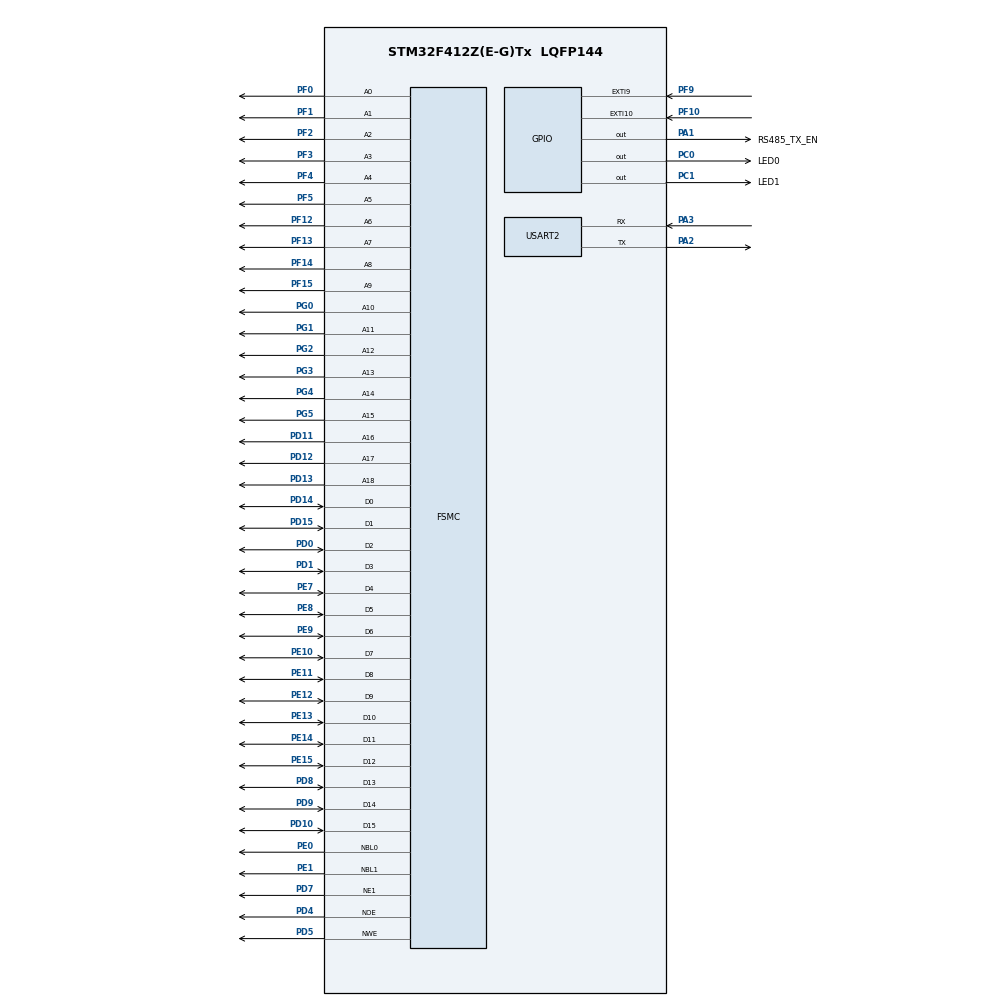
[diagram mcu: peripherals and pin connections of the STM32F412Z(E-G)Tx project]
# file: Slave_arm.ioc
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FSMC.AddressSetupTime1=0x00
FSMC.BusTurnAroundDuration1=0x00
FSMC.DataSetupTime1=0x06
FSMC.ExtendedAddressSetupTime1=0x00
FSMC.ExtendedBusTurnAroundDuration1=0x00
FSMC.ExtendedDataSetupTime1=0x06
FSMC.ExtendedMode1=FSMC_EXTENDED_MODE_ENABLE
FSMC.WriteFifo1=FSMC_WRITE_FIFO_DISABLE
FSMC.WriteOperation1=FSMC_WRITE_OPERATION_ENABLE
Mcu.Family=STM32F4
Mcu.Name=STM32F412Z(E-G)Tx
Mcu.Package=LQFP144
NVIC.EXTI15_10_IRQn=true\:2\:1\:true\:false\:true\:true\:true\:true
NVIC.EXTI9_5_IRQn=true\:3\:2\:true\:false\:true\:true\:true\:true
NVIC.PriorityGroup=NVIC_PRIORITYGROUP_2
NVIC.TIM2_IRQn=true\:3\:3\:true\:false\:true\:true\:true\:true
NVIC.TIM3_IRQn=true\:3\:1\:true\:false\:true\:true\:true\:true
NVIC.USART2_IRQn=true\:1\:3\:true\:false\:true\:true\:true\:true
PA1.GPIO_Label=RS485_TX_EN
PA1.GPIO_Speed=GPIO_SPEED_FREQ_HIGH
PA1.PinState=GPIO_PIN_SET
PA1.Signal=GPIO_Output
PA13.Mode=Serial_Wire
PA13.Signal=SYS_JTMS-SWDIO
PA14.Mode=Serial_Wire
PA14.Signal=SYS_JTCK-SWCLK
PA2.GPIO_ModeDefaultPP=GPIO_MODE_AF_PP
PA2.GPIO_PuPd=GPIO_NOPULL
PA2.GPIO_Speed=GPIO_SPEED_FREQ_HIGH
PA2.Mode=Asynchronous
PA2.Signal=USART2_TX
PA3.GPIO_ModeDefaultPP=GPIO_MODE_AF_PP
PA3.GPIO_PuPd=GPIO_PULLUP
PA3.GPIO_Speed=GPIO_SPEED_FREQ_HIGH
PA3.Mode=Asynchronous
PA3.Signal=USART2_RX
PC0.GPIO_Label=LED0
PC0.GPIO_PuPd=GPIO_PULLUP
PC0.GPIO_Speed=GPIO_SPEED_FREQ_HIGH
PC0.PinState=GPIO_PIN_SET
PC0.Signal=GPIO_Output
PC1.GPIO_Label=LED1
PC1.GPIO_PuPd=GPIO_PULLUP
PC1.GPIO_Speed=GPIO_SPEED_FREQ_HIGH
PC1.PinState=GPIO_PIN_SET
PC1.Signal=GPIO_Output
PC14-OSC32_IN.Mode=LSE-External-Oscillator
PC14-OSC32_IN.Signal=RCC_OSC32_IN
PC15-OSC32_OUT.Mode=LSE-External-Oscillator
PC15-OSC32_OUT.Signal=RCC_OSC32_OUT
PD0.GPIO_PuPd=GPIO_PULLDOWN
PD0.GPIO_Speed_High_Default=GPIO_SPEED_FREQ_HIGH
PD0.Signal=FSMC_D2_DA2
PD1.GPIO_PuPd=GPIO_PULLDOWN
PD1.GPIO_Speed_High_Default=GPIO_SPEED_FREQ_HIGH
PD1.Signal=FSMC_D3_DA3
PD10.GPIO_PuPd=GPIO_PULLDOWN
PD10.GPIO_Speed_High_Default=GPIO_SPEED_FREQ_HIGH
PD10.Signal=FSMC_D15_DA15
PD11.GPIO_PuPd=GPIO_PULLDOWN
PD11.GPIO_Speed_High_Default=GPIO_SPEED_FREQ_HIGH
PD11.Signal=FSMC_A16
PD12.GPIO_PuPd=GPIO_PULLDOWN
PD12.GPIO_Speed_High_Default=GPIO_SPEED_FREQ_HIGH
PD12.Signal=FSMC_A17
PD13.GPIO_PuPd=GPIO_PULLDOWN
PD13.GPIO_Speed_High_Default=GPIO_SPEED_FREQ_HIGH
PD13.Signal=FSMC_A18
PD14.GPIO_PuPd=GPIO_PULLDOWN
PD14.GPIO_Speed_High_Default=GPIO_SPEED_FREQ_HIGH
PD14.Signal=FSMC_D0_DA0
PD15.GPIO_PuPd=GPIO_PULLDOWN
PD15.GPIO_Speed_High_Default=GPIO_SPEED_FREQ_HIGH
PD15.Signal=FSMC_D1_DA1
PD4.GPIO_PuPd=GPIO_PULLDOWN
PD4.GPIO_Speed_High_Default=GPIO_SPEED_FREQ_HIGH
PD4.Signal=FSMC_NOE
PD5.GPIO_PuPd=GPIO_PULLDOWN
PD5.GPIO_Speed_High_Default=GPIO_SPEED_FREQ_HIGH
PD5.Signal=FSMC_NWE
PD7.GPIO_Speed_High_Default=GPIO_SPEED_FREQ_HIGH
PD7.Mode=NorPsramChipSelect1_1
PD7.Signal=FSMC_NE1
PD8.GPIO_PuPd=GPIO_PULLDOWN
PD8.GPIO_Speed_High_Default=GPIO_SPEED_FREQ_HIGH
PD8.Signal=FSMC_D13_DA13
PD9.GPIO_PuPd=GPIO_PULLDOWN
PD9.GPIO_Speed_High_Default=GPIO_SPEED_FREQ_HIGH
PD9.Signal=FSMC_D14_DA14
PE0.GPIO_Speed_High_Default=GPIO_SPEED_FREQ_HIGH
PE0.Signal=FSMC_NBL0
PE1.GPIO_Speed_High_Default=GPIO_SPEED_FREQ_HIGH
PE1.Signal=FSMC_NBL1
PE10.GPIO_Speed_High_Default=GPIO_SPEED_FREQ_HIGH
PE10.Signal=FSMC_D7_DA7
PE11.GPIO_Speed_High_Default=GPIO_SPEED_FREQ_HIGH
PE11.Signal=FSMC_D8_DA8
PE12.GPIO_Speed_High_Default=GPIO_SPEED_FREQ_HIGH
PE12.Signal=FSMC_D9_DA9
PE13.GPIO_Speed_High_Default=GPIO_SPEED_FREQ_HIGH
PE13.Signal=FSMC_D10_DA10
PE14.GPIO_Speed_High_Default=GPIO_SPEED_FREQ_HIGH
PE14.Signal=FSMC_D11_DA11
PE15.GPIO_Speed_High_Default=GPIO_SPEED_FREQ_HIGH
PE15.Signal=FSMC_D12_DA12
PE7.GPIO_Speed_High_Default=GPIO_SPEED_FREQ_HIGH
PE7.Signal=FSMC_D4_DA4
PE8.GPIO_Speed_High_Default=GPIO_SPEED_FREQ_HIGH
PE8.Signal=FSMC_D5_DA5
PE9.GPIO_Speed_High_Default=GPIO_SPEED_FREQ_HIGH
PE9.Signal=FSMC_D6_DA6
PF0.GPIO_Speed_High_Default=GPIO_SPEED_FREQ_HIGH
PF0.Signal=FSMC_A0
PF1.GPIO_Speed_High_Default=GPIO_SPEED_FREQ_HIGH
PF1.Signal=FSMC_A1
PF10.GPIO_PuPd=GPIO_NOPULL
PF10.Signal=GPXTI10
PF12.GPIO_Speed_High_Default=GPIO_SPEED_FREQ_HIGH
PF12.Signal=FSMC_A6
PF13.GPIO_Speed_High_Default=GPIO_SPEED_FREQ_HIGH
PF13.Signal=FSMC_A7
PF14.GPIO_Speed_High_Default=GPIO_SPEED_FREQ_HIGH
PF14.Signal=FSMC_A8
PF15.GPIO_Speed_High_Default=GPIO_SPEED_FREQ_HIGH
PF15.Signal=FSMC_A9
PF2.GPIO_Speed_High_Default=GPIO_SPEED_FREQ_HIGH
PF2.Signal=FSMC_A2
PF3.GPIO_Speed_High_Default=GPIO_SPEED_FREQ_HIGH
PF3.Signal=FSMC_A3
PF4.GPIO_Speed_High_Default=GPIO_SPEED_FREQ_HIGH
PF4.Signal=FSMC_A4
PF5.GPIO_Speed_High_Default=GPIO_SPEED_FREQ_HIGH
PF5.Signal=FSMC_A5
PF9.GPIO_PuPd=GPIO_NOPULL
PF9.Signal=GPXTI9
PG0.GPIO_Speed_High_Default=GPIO_SPEED_FREQ_HIGH
PG0.Signal=FSMC_A10
PG1.GPIO_Speed_High_Default=GPIO_SPEED_FREQ_HIGH
PG1.Signal=FSMC_A11
PG2.GPIO_Speed_High_Default=GPIO_SPEED_FREQ_HIGH
PG2.Signal=FSMC_A12
PG3.GPIO_Speed_High_Default=GPIO_SPEED_FREQ_HIGH
PG3.Signal=FSMC_A13
PG4.GPIO_Speed_High_Default=GPIO_SPEED_FREQ_HIGH
PG4.Signal=FSMC_A14
PG5.GPIO_Speed_High_Default=GPIO_SPEED_FREQ_HIGH
PG5.Signal=FSMC_A15
PH0\ -\ OSC_IN.Mode=HSE-External-Oscillator
PH0\ -\ OSC_IN.Signal=RCC_OSC_IN
PH1\ -\ OSC_OUT.Mode=HSE-External-Oscillator
PH1\ -\ OSC_OUT.Signal=RCC_OSC_OUT
ProjectManager.HeapSize=0x00000200
ProjectManager.StackSize=0x00001000
ProjectManager.TargetToolchain=STM32CubeIDE
RCC.AHBFreq_Value=100000000
RCC.APB1CLKDivider=RCC_HCLK_DIV2
RCC.APB1Freq_Value=50000000
RCC.APB1TimFreq_Value=100000000
RCC.APB2Freq_Value=100000000
RCC.APB2TimFreq_Value=100000000
RCC.CortexFreq_Value=100000000
RCC.HCLKFreq_Value=100000000
RCC.HSE_VALUE=25000000
RCC.PLLM=25
RCC.PLLN=400
RCC.PLLP=RCC_PLLP_DIV4
RCC.PLLSourceVirtual=RCC_PLLSOURCE_HSE
RCC.SYSCLKFreq_VALUE=100000000
RCC.SYSCLKSource=RCC_SYSCLKSOURCE_PLLCLK
RCC.USBFreq_Value=200000000
RCC.VCOOutputFreq_Value=400000000
SH.FSMC_A0.0=FSMC_A0,19b-a1
SH.FSMC_A1.0=FSMC_A1,19b-a1
SH.FSMC_A10.0=FSMC_A10,19b-a1
SH.FSMC_A11.0=FSMC_A11,19b-a1
SH.FSMC_A12.0=FSMC_A12,19b-a1
SH.FSMC_A13.0=FSMC_A13,19b-a1
SH.FSMC_A14.0=FSMC_A14,19b-a1
SH.FSMC_A15.0=FSMC_A15,19b-a1
SH.FSMC_A16.0=FSMC_A16,19b-a1
SH.FSMC_A17.0=FSMC_A17,19b-a1
SH.FSMC_A18.0=FSMC_A18,19b-a1
SH.FSMC_A2.0=FSMC_A2,19b-a1
SH.FSMC_A3.0=FSMC_A3,19b-a1
SH.FSMC_A4.0=FSMC_A4,19b-a1
SH.FSMC_A5.0=FSMC_A5,19b-a1
SH.FSMC_A6.0=FSMC_A6,19b-a1
SH.FSMC_A7.0=FSMC_A7,19b-a1
SH.FSMC_A8.0=FSMC_A8,19b-a1
SH.FSMC_A9.0=FSMC_A9,19b-a1
SH.FSMC_D0_DA0.0=FSMC_D0,16b-d1
SH.FSMC_D10_DA10.0=FSMC_D10,16b-d1
SH.FSMC_D11_DA11.0=FSMC_D11,16b-d1
SH.FSMC_D12_DA12.0=FSMC_D12,16b-d1
SH.FSMC_D13_DA13.0=FSMC_D13,16b-d1
SH.FSMC_D14_DA14.0=FSMC_D14,16b-d1
SH.FSMC_D15_DA15.0=FSMC_D15,16b-d1
SH.FSMC_D1_DA1.0=FSMC_D1,16b-d1
SH.FSMC_D2_DA2.0=FSMC_D2,16b-d1
SH.FSMC_D3_DA3.0=FSMC_D3,16b-d1
SH.FSMC_D4_DA4.0=FSMC_D4,16b-d1
SH.FSMC_D5_DA5.0=FSMC_D5,16b-d1
SH.FSMC_D6_DA6.0=FSMC_D6,16b-d1
SH.FSMC_D7_DA7.0=FSMC_D7,16b-d1
SH.FSMC_D8_DA8.0=FSMC_D8,16b-d1
SH.FSMC_D9_DA9.0=FSMC_D9,16b-d1
SH.FSMC_NBL0.0=FSMC_NBL0,2ByteEnable1
SH.FSMC_NBL1.0=FSMC_NBL1,2ByteEnable1
SH.FSMC_NOE.0=FSMC_NOE,Sram1
SH.FSMC_NWE.0=FSMC_NWE,Sram1
TIM2.AutoReloadPreload=TIM_AUTORELOAD_PRELOAD_ENABLE
TIM2.Period=1000-1
TIM2.Prescaler=100-1
TIM3.AutoReloadPreload=TIM_AUTORELOAD_PRELOAD_ENABLE
TIM3.Period=10000-1
TIM3.Prescaler=50-1
USART2.VirtualMode=VM_ASYNC
VP_TIM2_VS_ClockSourceINT.Mode=Internal
VP_TIM3_VS_ClockSourceINT.Mode=Internal
board=custom

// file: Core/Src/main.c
/* USER CODE BEGIN Header */
/**
  ******************************************************************************
  * @file           : main.c
  * @brief          : Main program body
  ******************************************************************************
  * @attention
  *
  * Copyright (c) 2024 STMicroelectronics.
  * All rights reserved.
  *
  * This software is licensed under terms that can be found in the LICENSE file
  * in the root directory of this software component.
  * If no LICENSE file comes with this software, it is provided AS-IS.
  *
  ******************************************************************************
  */
/* USER CODE END Header */
#include "main.h"
#include "tim.h"
#include "usart.h"
#include "gpio.h"
#include "fsmc.h"

/* USER CODE BEGIN Includes */
#include "sys.h"
#include "led.h"
#include "KesaiAPI.h"
#include "comm.h"
#include "base.h" /* 基本结构 */
#include "stdio.h"
#include "stdafx.h"
//#include "KS_FB_VISU.h"/* VISU相关 */
#include "KS_FB_ProSample.h"/* 采样处理及计算误�??? */
#include "KS_FB_ProSample_v2.h"
//新飞点剔除模块(总开关KS_USE_NEW_FLY_REMOVE在此头文件内)|Yang.zj+用于新飞点检测 2026.10.24.103254
#include "ks_fly_remove.h"
//#include "AutoFindTaps.h"
#include "calcerr.h"
#include "calcbase.h"
/* 2024.02.01.110058 同步 liu.yt */
#include "StRingNet.h"  /* 2024.1.18.153154/han.dp/+ */
#include "StFileOp.h"
#include "bin_upgrade.h"
#include "ks_somefunc.h"

//2025.7.22.105132|wei.n
#include "modbus485.h"
#include "KS_FB_RoundSample.h"/*粗采样处理及显示处理*/
#include "KS_FB_DacOutCtl.h"
#include "string.h"
//全自动套印色标检测(总开关USE_MARK_DETECTION在markDetection.h,暂未投用默认0整体不编译;
//include必须无条件保留——宏定义在头文件内,若此处也加#if会把宏锁死在未定义(恒0),启用失效
// |Yang.zj+markDetection封编译宏 2026.11.13.120400)
#include "markDetection.h"

// 2026.5.20.100908 宏定义：1 = 使用新版 KS_FB_ProSample_V2，0 = 使用旧版 KS_FB_ProSample，
#define USE_PROSAMPLE_V2  0

/* USER CODE END Includes */

/* USER CODE BEGIN PV */

EXCEPTION_OF_CRASH exception_crash;/* 主机死机信息/2024.1.20.142743/han.dp/+ */
uint8_t byReqRdExceptionOfProgCrash = 0;/* =1.send Mailbox cmd to master-station. and echo ack message./2024.1.18.105623/han.dp */
unsigned char g_bygetsts = 0;/* =0 idle =1 给上位机信号 抓取死机信息 */
							 /* =2 获取抓取到信�??? =3 获取成功 =4 获取超时@10�??? */
unsigned short g_getcrash_inf_timecnt_10ms = 0;/* 10ms计时计数值@用于获取死机信息计时 */
char g_send_crashinf_hmi = 0;

static WORD g_wCnt_Rs = 0;
static INT g_iRtn_Calc2022 = 0;
static INT g_aiVResult[2] = {0};
static INT g_aiHResult[2] = {0};

INT Perimeter = 500;
INT Coordinate = 4000;
static BYTE iStationId=240;                                         /* 站号获取 */
/* 2021.8.14.152254=-------------------------------------------------2021.8.14.152306判断定时器无标志，只做计数增�??? */
static WORD g_wCount_Comm;											/* 主从通讯 */
//static WORD g_wCount_Visu;											/* 485通讯 */
static WORD g_wCount_CaseBase;										/* 计算基线 */
//static WORD g_wCount_TimeOut;										/* 485超时计数 */
static WORD g_wCount_FeedDog;										/* 喂狗计数 */
static WORD g_iCount_TimeOutNum;									/* 超时计次 */
static WORD g_uiDelayTime_Init=0;//2025.7.25.160145+
static WORD g_uiTime_DigitalTubes=0;								/*2025.09.06.151705//xi.hy//数码管显示计数*/
static WORD g_uiTime_LED1_Flick=0;//2025.11.5.183542+

//2025.11.28.130828//自动聚焦_偏移自调整相关计数变量
static WORD g_uiTime_OffsetAutoCtl;//偏移自调整控制计数
static WORD g_uiTime_xBaseDone_OffsetAutoCtl;//基线稳定计数
static DWORD g_dwRemainTime_OffsetCtl;//本次调整持续时间
//2025.12.01.165834//自动聚焦_光源自调整相关计数变量
static WORD g_uiCtlTime_SourceLightCtl;//光源控制时间计数
static WORD g_uiTime_PeakDone_SourceAutoCtl;//光源控制到目标时间计数
static DWORD g_dwRemainTime_SourceCtl;//本次光源自调持续时间计数
//INT aiFineData1[4000];												/* 精采样�?? */
//INT aiFineData2[4000];												/* 精采样�?? */
unsigned short tmp;
//extern unsigned char byReceiveEnd;									/* 接收完成标志，根据接收数据量与CRC校验判断 */
//extern DWORD dwRoundSampleThreshold;								/* 主站接收到的粗采样阀�???*/
uint8_t* pbyRoundData2;												/* 粗采样第二路信号地址**便于保存文件 */
uint8_t* pbyRoundData1;												/* 粗采样第�???路信号地�???**便于保存文件 */
static BYTE byFineSampleSaveFlag;									/* 主站下发的保存采样按�???*/
static INT aiError_V[40];											/* 2020.05.04.171022|niu.j|误差存入循环队列，等待发送时读取索引，判断误差刷新幅数，根据幅数发�?�误差个�???*/
static INT aiError_H[40];
static BYTE byScanCount=0;
//static BYTE byScanCountPre=0;
static unsigned short FeedDogAdr=0x054;								/* 喂狗地址*/
static unsigned short FeedDog=0x5555;								/* 喂狗�???*/
static unsigned short wArmResetCountAdr=0x500;						/* 看门狗复位计数地�??? */
static unsigned short wArmResetCount;								/* 看门狗复位计�??? */
static REAL alrThreshold[2];										/* 采样显示�???�??? */
static REAL alrBase_Fs[2];											/* 精采样计算基�??? */
INT iRtnRdID;
//extern BYTE RS485_RX_BUFF[150];										/* 读取到的485数据 */
WORD ErrNum;														/* 错误计次 */
//BYTE abyRoundSampleData_485[1600];									/* 发�?�波形使用缓冲区 */
//static BYTE abyMinData_Sample[2] ;									/* 两路信号�???小�??-2021.9.16.105149通讯到人机处理波形显�??? */

//extern WORD wSendNum_Test;											/* 485发�?�计�???2021.8.20.103739 */
//extern WORD wReadNum_Test;											/* 485接收计次2021.8.20.103749 */
//2025.7.23.104353+
static uint8_t bySignalSelect_Pre = 0 ;
static uint16_t ChangeRGBAdr = 0x5040;							//切换RGB通道的地址
uint16_t uiValue_RGB = 0;
/* 2023.09.18.113506 定义 */
unsigned int dwAdrStAutoFind_wwz_IN,dwAdrStAutoFind_wwz_OUT;

//2025.7.23.195236 移动到全局@就相当于对结构体初始化
StAxisParam stStAxisParam;													/* 轴参�??? */
StGrpParam stStGrpParam;														/* 系参�??? */
StGlobalParam stStGlobalParam;												/* 整机参数 */
StSyncWithServerOut stStSyncWithServerOut;									/* 通讯相关变量 */
StPara_PduBroadcastUp stStPara_PduBroadcastUp;								/* 通讯数据|UP */
StPara_PduBroadcastDn stStPara_PduBroadcastDn;								/* 通讯数据|Dn */
/* USER CODE END PV */

void SystemClock_Config(void);
/* USER CODE BEGIN PFP */
/* 2024.02.01.155049 死机时获取信息函�??? */
/* pxgeten 使用的轴参数中的i_pstStAxisParam->wButtonFun.15| */
void ks_get_prgcrash_inf(short iStationId,/* 本地站号的接口好像没用，先留�???�??? */
						char* pxgeten,
						unsigned char* pbygetsts,
						unsigned short* pgetcrash_inf_timecnt_10ms,
						LP_EXCEPTION_OF_CRASH pcrash_inf)
{
	unsigned char bygetsts,xgeten;
	unsigned short crash_inf_adrsa = 0x3e00;/* 死机信息的起始地�??? */
	unsigned short getcrash_inf_timecnt_10ms;
	static unsigned char timeout_cnt;/* 超时计数 */
	StFunction get_inf;/* 获取死机信息时需要发送的内容结构体@主要是m_id=0x400; */
	get_inf.m_id = 0x400;
	/* 计算dword的个�??? */
	signed int inf_lenth=sizeof(EXCEPTION_OF_CRASH);
	if(inf_lenth % 4 ==0 ) inf_lenth = inf_lenth/4;
	else inf_lenth = inf_lenth/4+1;

	if(pbygetsts!=0 && pcrash_inf!=0 && pxgeten!=0 &&  pgetcrash_inf_timecnt_10ms!=0)
	{
		bygetsts = *pbygetsts;/* 拿到当前状�?�|=1 向主站写入获取命令�?��?? */
		xgeten = *pxgeten;
		getcrash_inf_timecnt_10ms = *pgetcrash_inf_timecnt_10ms;
		if(xgeten)
		{/* 获取标志有效�??? */
			xgeten = 0;
			if(bygetsts==3 || bygetsts==4 || bygetsts==0)/* 在初始状�???,或着完成状�?�|超时状�?�可以重新开�??? */
				bygetsts = 1;
		}
		else
		{/* 未使�??? */
			;
		}
		switch (bygetsts)
		{
			case 0:/* 初始状�?? */
				break;
			case 1:/* 向主站写入获取命�??? */
				/* 给主站触发请�???,通过mailbox通讯 */
				GT_RN_DevicePcMailComWr((unsigned long *) & (get_inf), 0, 0, 2, RN_LMWR, 1);/* RN_LMWR 起始地址无意�??? */
				/* inf_lenth 这个变量是dword的个�???,使用sizeof获取@2024.06.07.090154 */
				memset((void*)pcrash_inf,0,(int32)(sizeof(EXCEPTION_OF_CRASH))/*inf_lenth*/);/* 初始化信�??? */
				bygetsts = 2;
				getcrash_inf_timecnt_10ms =0 ;/* 清零计时�??? */
				timeout_cnt = 0;
				break;
			case 2:/* 定时�???�??? 获取的信息写入区域@起始地址0x3E00 */
				if(getcrash_inf_timecnt_10ms>=100)/* 100*10ms */
				{
					getcrash_inf_timecnt_10ms = 0;
					GT_RN_DevicePcMailComRd((unsigned long *) pcrash_inf, 0, crash_inf_adrsa, inf_lenth, RN_ARD);/* RN_ARD |绝对寻址 */
					if(pcrash_inf->wYear!=0)/* 获取到了信息*/
					{
						bygetsts = 3;
					}
					else
					{
						timeout_cnt = timeout_cnt+1;/* 超时+1*/
					}

					if (timeout_cnt>=10)/* 10次超�???*/
					{
						bygetsts = 4;
					}
				}
				break;
			case 3:/* 获取完成�??? */
				break;
			case 4:/* 获取超时�???*/
				break;
			default:
				break;
		}
		*pbygetsts = bygetsts;
		*pxgeten = xgeten;
		*pgetcrash_inf_timecnt_10ms = getcrash_inf_timecnt_10ms;
	}
}
/* ********************************************************获取死机信息@2024.02.01.224710-end */

/* 2024.9.28.141504/wei.n/外部中断的回调函数 */
void HAL_GPIO_EXTI_Callback(uint16_t GPIO_Pin)
{
	if(GPIO_Pin == GPIO_PIN_9)
	{
		__HAL_GPIO_EXTI_CLEAR_IT(EXTI_LINE_9); /* 清除LINE9上的中断标志位 */
	}
	else
	{
		__HAL_GPIO_EXTI_CLEAR_IT(EXTI_LINE_10); /* 清除LINE10上的中断标志位 */
		RingNetRxPacketThread(0);
	}
}

/* +注释 10ms计时器@2024.02.01.221826 */
/* 2024.7.31.115331/wei.n/TIM3的中断函�??? */
//已经验证过了,time3的计时周期为10ms@2025.11.5.125252确认
//调整一些计时的宏
void TIM3_IRQHandler(void)
{
	//2025.11.5.125159+
	//获取更新中断宏使用错误@用成了更新中断使能标志获取宏
	//if(__HAL_TIM_GET_IT_SOURCE(&htim3, TIM_IT_UPDATE) == SET)  /* 溢出中断 */
	if(__HAL_TIM_GET_FLAG(&htim3, TIM_FLAG_UPDATE) )//更新中断有效
	{
		__HAL_TIM_CLEAR_FLAG(&htim3, TIM_FLAG_UPDATE);//清除更新中断标志
		HAL_TIM_IRQHandler(&htim3);

		g_wCount_Comm= g_wCount_Comm+1;
		//g_wCount_Visu= g_wCount_Visu+1;
		g_wCount_CaseBase= g_wCount_CaseBase+1;
		g_wCount_FeedDog= g_wCount_FeedDog+1;
		/* 2024.02.01.221659 增加获取死机信息计时�??? */
		g_getcrash_inf_timecnt_10ms = g_getcrash_inf_timecnt_10ms+1;

		//2025.7.22.175420+
		g_uiCycleCommTimer = g_uiCycleCommTimer + 10;//485通讯计时@5ms
		g_uiTimeOutTimer += 10;//通讯超时计时
		g_uiPollTimer += 10;//轮询计时
		//2025.7.25.155941 初始化等待@月光宝盒\月光宝盒pro中站号的eerom启动比较慢,增加个延时再读取|临时方案
		g_uiDelayTime_Init += 10;

		//数码管显示站号轮询
		//2025.09.06.141720//xi.hy
		g_uiTime_DigitalTubes += 10;

		g_uiTime_LED1_Flick += 10;
		//LED0 = !LED0;

		//自动聚焦_偏移自调整计数
		g_uiTime_OffsetAutoCtl+=10;
		g_uiTime_xBaseDone_OffsetAutoCtl+=10;
		g_dwRemainTime_OffsetCtl+=10;
		//自动聚焦_光源自调整计数
		g_uiCtlTime_SourceLightCtl+=10;//光源控制时间计数地址
		g_uiTime_PeakDone_SourceAutoCtl+=10;//光源控制到目标时间计数地址
		g_dwRemainTime_SourceCtl+=10;//本次光源自调持续时间计数地址
	}
	//2025.11.5.124942 清除的宏定义使用错误
	//__HAL_TIM_CLEAR_IT(&htim3, TIM_IT_UPDATE);  /* 清除中断标志�??? */
}

/* USER CODE END PFP */

int main(void)
{

  /* MCU Configuration--------------------------------------------------------*/

  /* Reset of all peripherals, Initializes the Flash interface and the Systick. */
  HAL_Init();

  /* Configure the system clock */
  SystemClock_Config();

  /* Initialize all configured peripherals */
  MX_GPIO_Init();
  /* USER CODE BEGIN 2 */
  //HAL_NVIC_SetPriorityGrouping(NVIC_PRIORITYGROUP_2);/* 设置系统中断优先级分�???2 */
  MX_LED_Init();									 /* LED初始�??? */
  MX_FSMC_Init();
  GTD_Open(Bank1_SRAM3_ADDR);
  tmp = 0;

  MX_USART2_UART_Init(); 	/* 485初始化，APB1时钟1/4系统时钟频率,25HZ */
  MX_TIM3_Init();   		/* 10ms */
  MX_TIM2_Init();			/* 该定时器用于增加接收与发送数据包之间的间�???-100us-1000us,根据设定值不�??? */

  /********************************************************/

  while(iStationId<1 || iStationId>31)				/* 站号读取成功 */
  {
	  if(g_uiDelayTime_Init >= 1000)//超过1s后执行 EEROM启动有点慢 临时处理@针对月光宝盒\月光宝盒pro|2025.7.25.160355
	  {
		  //g_uiDelayTime_Init = 1000;//防止溢出
		  iRtnRdID= GT_RN_GetLocalID(&iStationId);
	  }

  }

	while( (tmp & 0x4000) == 0x0000)					/* 读取主站DSP启动标志 */
	{
		if(g_uiDelayTime_Init>1000)//2025.11.29.155702+增加1s sleep|没开主站的时候有可能在线升级不成功
		{
			g_uiDelayTime_Init = 0;//2025.11.29.155802+ 重新计时
			iRtnRdID = GT_RN_MailRdMultReg(2, &tmp, 1, 1, 0);
			if(iRtnRdID)
			{
				tmp = 0;
			}
			/* 从站等待主站响应过程中，�???直喂�??? */
			GT_RN_WriteFPGA(FeedDogAdr, &FeedDog);
		}
	}

  /* 用于看门狗计�??? */
  GT_RN_ReadFPGA(wArmResetCountAdr,&wArmResetCount);							/* 从FPGA中先读出计数�??? */
  wArmResetCount=wArmResetCount+1;
  GT_RN_WriteFPGA(wArmResetCountAdr,&wArmResetCount);							/* +1后再写入进去 */
 //激活本地粗采样
  KS_InitSample(iStationId);
  static BYTE xGetAxisId;														/* 获取站号 */
  BYTE byLedSwitchTimeouts;														/* 屏保延时 */
 // static INT iJourney_HorzRapidAdjust;											/* 横向快�?�丢�??? */
  //static DWORD  dwPlateAdjustmentProf;											/* 快�?�对版�?? */
  INT iRoundSampleFlag;															/* 实际粗采样数据采集到�??? */
  INT iFineSampleFlag;															/* 实际精采样数据采集到�??? */
  static BYTE xStart;															/* 程序首次运行标志 */
  uint8_t* pbyFineData2;															/* 粗采样第二路信号地址 */
  uint8_t* pbyFineData1;															/* 粗采样第�???路信号地�??? */
  static REAL alrBase[2];														/* 两路波形的基�??? */
  static REAL alrBase_HMI[2];													/* 两路波形的基�??? */
  static BYTE xInclNegative10vSignal;											/* 处理±10V电眼 */
  INT iN;																	/* 循环变量 */
  INT* piItem1;
  INT* piItem2;
  static INT aiFineSample_Data[9];												/* 通讯给主站的波形细节 */
  static BYTE bySignal10VCoef;													/* ±10V光电眼IO控制 */
  BYTE xFlag_CopyFromMaster;													/* 主站参数更新完成标志，用�???485通讯使能 */

  BYTE xOK_FromMaster;
  static BYTE test;

  //BYTE bySample_Interval;														/* 采样间隔-放大�???2，不放大5 */
  static BYTE xFlag_SingleMode;
  //BYTE xMarkHor;																/* 门内基线标志 */
  DINT diFineSampleStart;
  INT iGateWidthFinePt = 1000;//精彩样点数值@2025.7.15.183713+
	// 2025.7.22.103936|wei.n|添加
	uint8_t*	pbyRoundData1;									/*粗采样第�???路信号地�???*/
	uint8_t*	pbyRoundData2;									/*粗采样第二路信号地址*/
	uint8_t*	pbyRoundData3;									/*粗采样第�???路信号地�???*/
	uint8_t*	pbyRoundData4;									/*粗采样第二路信号地址*/
	uint8_t*	pbyRoundData5;									/*粗采样第�???路信号地�???*/
	uint8_t*	pbyRoundData6;
	uint8_t xCalcBaseLine = FALSE;
	uint8_t xUpdateRsData_Hmi = FALSE;//更新界面粗采样数据
	uint8_t xDealRsData = FALSE;
	uint8 byRoundId = 0;//当前粗采样轮询id
	uint8_t bySignalSelect_Cur = 0;//当前轮询RGB通道
	uint8_t byChannel_T1T2_Cur = 0;//当前轮询T1 T2通道
	uint8_t xDealRsDataDne = FALSE;
	//2025.12.03.152331//自动聚焦相关局部变量定义
	uint8_t xFindFSPeak_SourceLightCtl=FALSE;

  bySignalSelect_Pre = stStGlobalParam.bySignalSelect +1 ;//上电后写入一次

  while (1)
  {

	//在20ms周期任务中执行@2025.6.11.124050+
	//油墨槽脉冲输出控制变量定义
	BYTE xPulseCtlEn = FALSE;//脉冲控制使能
	BYTE xPulseOutEn_Act = FALSE;//脉冲输出使能了
	BYTE xMoveDir_Act = FALSE;//运动方向
	BYTE xPulseCtlMode_Act = FALSE;//脉冲控制模式
	BYTE xVelMod_Run_Act = FALSE;//速度模式,速度使能标志
	REAL rVelMod_Vel_Act = 0;//速度模式下的速度
	WORD wPosMod_Pulse_Act = 0;//位置模式下实际的脉冲数
	WORD wPulse_1r = 0;//1圈的脉冲数
	WORD wTmp = 0;
	//DINT diThisMovePluse = 0;//2025.6.11.232404 本次运动的距离
	Lp_StInkGrooveCtl pstStInkGrooveCtl = 0;

	  /* ----------------------------------------------------sj 2021.8.20.105400--------------�???部变量定义完�???--------------------------- */
	  //2025.09.06.151737//xi.hy//数码管显示站号处理
	  KS_ShowId_DigitalTubes(iStationId,
			  	  	  	  	  &g_uiTime_DigitalTubes,
							  xFlag_CopyFromMaster);

		//运行指示(LED1)@2025.10.29.164927+
		if(xFlag_CopyFromMaster)//主站通讯成功按照500ms闪烁@周期是1s
			KS_Led1Flick(500,&g_uiTime_LED1_Flick);
		else//运行了就按照2s闪烁@周期是4s
			KS_Led1Flick(2000,&g_uiTime_LED1_Flick);

	  /* 2022.6.21.090345 -判断站号31�???-不进入以下�?�辑-进入到副主站485通讯 */
	  if(iStationId!=31)//2025.7.24.203934 增加了主站通讯完成标志
	  {
		  //2025.11.4.114411 屏蔽
		  //GT_RN_SetSenceDO((WORD)bySignal10VCoef);								/* ±10V光电眼两路IO控制 */
		  //bySample_Interval = 5;
		  /* 主�?�辑里面500ms喂一次狗 */
		  if(g_wCount_FeedDog>=50&&test==0)
		  {
			  GT_RN_WriteFPGA(FeedDogAdr, &FeedDog);
			  g_wCount_FeedDog=0;
		  }

		/* 看门�???-喂狗结束2021.8.20.105514 */

		/* -----------------------------2021.1.5.153657---------横排打开后，基线�???要用精采样基线，获取门内基线�???�??? */
		//xMarkHor = GetBit(stStAxisParam.wSwitchRef,1);
		//xMarkHor = KSGetDataBit(&stStAxisParam.wSwitchRef,1);
		/* -----------------------------------------------------计算偏移�??? */
		stStAxisParam.iARMRunNum=0;		/* 2022.5.21.084425 */
		/* 2021.8.20.112017-------------------------------------粗采样处�???--------------------------------------- */
		/* 读取粗采样数据有效标�??? */
		//GT_RN_SampleGetRoundData((void**)&pbyRoundData2, (void**)&pbyRoundData1, &iRoundSampleFlag);
		//2025.7.22.102737|wei.n|移植
		GT_RN_SampleGetRoundData((void**)&pbyRoundData1, (void**)&pbyRoundData2, (void**)&pbyRoundData3, (void**)&pbyRoundData4, (void**)&pbyRoundData5, (void**)&pbyRoundData6, &iRoundSampleFlag);
		/* 粗采样数据到位后，每500ms处理�???次数�??? */
		/* 1.计算粗采样基�??? */
		/* 2.将两路信号处理为HMI显示�???用数�??? */

		//xUpdateRsData_Hmi = FALSE;
		if ( iRoundSampleFlag == 1 && !xDealRsData)//2025.9.2.122029+xDealRsData
		{
			stStAxisParam.uiRSampleCounter +=1;
			iRoundSampleFlag = 0;//清零粗采样标志
			//xUpdateRsData_Hmi = TRUE;//更新粗采样界面数据
			xDealRsData = TRUE;//处理粗采样数据@2025.8.6.183048+

			stStAxisParam.iARMRunNum=1;		/* 2022.5.21.084425 */
			//基线计算标志
			//xCalcBaseLine =FALSE;@修改到KsGetSampleInf_V2中复位
			if(g_wCount_CaseBase>=gc_Count_CalcBaseNum)
			{
			  xCalcBaseLine = TRUE;
			  g_wCount_CaseBase = 0;//重新计时
			}
			//2025.12.03.151915//xi.hy//自动聚焦/查找粗采样时需在粗采样有效后
			xFindFSPeak_SourceLightCtl=1;

			//  6个通道全部处理
//			  KsGetSampleInf(&stStGlobalParam,
//					  	  	  &stStAxisParam,
//					  	    xCalcBaseLine,//计算基线使能
//							alrBase_Fs,					//精采样基线
//							pbyRoundData1,				//粗采样T1_R起始地址
//							pbyRoundData2,				//粗采样T2_R起始地址
//							pbyRoundData3,				//粗采样T1_G起始地址
//							pbyRoundData4,				//粗采样T2_G起始地址
//							pbyRoundData5,				//粗采样T1_B起始地址
//							pbyRoundData6);				//粗采样T2_B起始地址)

		}
		//全自动套印代码
		//USE_MARK_DETECTION=0时调用点一并编译剔除(模块零RAM/Flash,见markDetection.h)|Yang.zj+markDetection封编译宏 2026.11.13.120400
#if USE_MARK_DETECTION
		KsAutoFindSignal(pbyRoundData1,				//粗采样T1_R起始地址
			pbyRoundData2,				//粗采样T2_R起始地址
			pbyRoundData3,				//粗采样T1_G起始地址
			pbyRoundData4,				//粗采样T2_G起始地址
			pbyRoundData5,				//粗采样T1_B起始地址
			pbyRoundData6,				//粗采样T2_B起始地址
			stStAxisParam.xFlag_AutoAdj_En,
			alrBase,					//基线值
			stStGlobalParam.bySignalSelect,//通道选择
			&stStAxisParam,
			1//(*套色传感器类型|=0 传统光电眼|=1 曜光接口(光纤电眼)*)
			);
#endif
	  //V2一个周期只处理一路@减小循环次数@单次4-5ms
	  KsGetSampleInf_V2(&xDealRsData,//轮询处理完后复位
					  &stStGlobalParam,
					  &stStAxisParam,
					  &stStGrpParam,//2026.4.22.152732+
					&xCalcBaseLine,//计算基线使能
					alrBase_Fs,					//精采样基线
					pbyRoundData1,					//粗采样T1_R起始地址
					pbyRoundData2,				//粗采样T2_R起始地址
					pbyRoundData3,				//粗采样T1_G起始地址
					pbyRoundData4,				//粗采样T2_G起始地址
					pbyRoundData5,				//粗采样T1_B起始地址
					pbyRoundData6,				//粗采样T2_B起始地址)
					&byRoundId,//轮询的id
					&bySignalSelect_Cur,//当前轮询RGB通道
					&byChannel_T1T2_Cur,//当前轮询T1 T2通道
					&xDealRsDataDne);//粗采样处理完成了

	  //在处理粗采样的时候按照当前轮询的id处理
	  xUpdateRsData_Hmi = FALSE;
	  if(xDealRsData || xDealRsDataDne)//xDealRsData标志在最后一个通道会清零,但是会置位完成标志
	  {
		  xDealRsDataDne = FALSE;//复位处理完成标志
		  xUpdateRsData_Hmi = TRUE;//更新粗采样界面数据
	  }

		//粗采样通道屏蔽处理|2025.7.22.104942|wei.n|
		KsRGBChannelCtl((uint8_t)(stStGlobalParam.uiSomeCtlBit_RW & 0x0007));

		//计算界面上波门宽度值
		if(xFlag_CopyFromMaster)//主从通讯正常了才能处理
			stStGlobalParam.iGateWidthRdPt_Hmi =
				KSGetGateWidth_Hmi(stStAxisParam.iGateWidthRondPt,stStGlobalParam.iScalPoints_HorScal,KSGetDataBit(&stStGlobalParam.uiSomeCtlBit_RW,3));

		//2025.7.22.105009|wei.n|
		pbyFineData1 = (uint8_t*) stStGlobalParam.auiFSDataT1;
		pbyFineData2 = (uint8_t*) stStGlobalParam.auiFSDataT2;

		/* 读取精采样数据有效标�??? */
		if(byFineSampleSaveFlag==0)	/* 非采样保存过程中读取精采样数�??? */
		{
			//切换精采样数据
			if(stStGlobalParam.bySignalSelect!= bySignalSelect_Pre)
			{
				//写入到fpga@s2025.7.26.155811 修改rgb通道切换控制方式
				uiValue_RGB = (uint16_t)stStGlobalParam.bySignalSelect;	//低4bit是控制T1当前rgb(b通道)|高4bit是控制T2当前rgb(a通道)
				iRtnRdID = GT_RN_WriteFPGA(ChangeRGBAdr, &uiValue_RGB);
#if KS_USE_NEW_FLY_REMOVE
				//RGB通道切换后信号源变化,原可信历史不可信,复位新飞点剔除器|
				//Yang.zj+用于新飞点检测 2026.10.24.103254
				KS_FlyRemove_Reset_V();
				KS_FlyRemove_Reset_H();
#endif
			}

			bySignalSelect_Pre=stStGlobalParam.bySignalSelect;

			//GT_RN_SampleGetFineData( pbyFineData2, pbyFineData1, &iFineSampleFlag );
			GT_RN_SampleGetFineData( pbyFineData1, pbyFineData2, &iFineSampleFlag );
		}
		else
			bySignalSelect_Pre = stStGlobalParam.bySignalSelect + 1;//保证下次进入的时候可以配置

		if( iFineSampleFlag == 1 )														/* 实际采样数据采集到位 */
		{
			//xInclNegative10vSignal = GetBit(stStAxisParam.wSwitchRef,9);
			if( xInclNegative10vSignal )												/* 处理±10V电眼信号 */
			{
				piItem1 = (INT*)pbyFineData1;
				piItem2 = (INT*)pbyFineData2;
				//2025.7.15.183816+
				iGateWidthFinePt = stStAxisParam.iGateWidthFinePt_Act;//2025.7.24.212435 使用实际精彩样点数
				if(iGateWidthFinePt<0) iGateWidthFinePt = 1000;
				for( iN=0; iN<iGateWidthFinePt; iN++ )//2025.7.15.183821 常量1000修改为变量
				{
					*piItem1 = *piItem1 + 32768;
					piItem1 = piItem1 + 1;

					*piItem2 = *piItem2 + 32768;
					piItem2 = piItem2 + 1;
				}
			}
			/* 计算误差处理 */
			/* 1.计算误差 */
			/* 2.误差平均 */
			/* 3.05#命令-误差上报 */
			stStAxisParam.iARMRunNum=9;		/* 2022.5.21.084425 */

			//xOK_FromMaster = GetBit(stStAxisParam.dwControlBits,4);								/* 单标记||2020.6.24.160749||niu.j|使用单元盒的处理 */
			xOK_FromMaster = KSGetDataBit(&stStAxisParam.dwControlBits,4);	/* 单标记||2020.6.24.160749||niu.j|使用单元盒的处理 */
			//粗采样基线获取@2025.7.25.102340
			alrBase[0] = stStGlobalParam.fBaseLine_T1;
			alrBase[1] = stStGlobalParam.fBaseLine_T2;

		#if USE_PROSAMPLE_V2

		  	KS_FB_ProSample_V2(
								&stStPara_PduBroadcastUp,  										/* 通讯参数，上 ??? */
								(WORD*)pbyFineData1,											/* 精采样数据地 ??? */
								(WORD*)pbyFineData2,											/* 精采样数据地 ??? */
								iFineSampleFlag,												/* 精采样有效标 */
								&stStAxisParam,													/* 轴参 ??? */
								&stStGrpParam,													/* 系参 ??? */
								alrBase,														/* 粗采样基 ??? */
								aiError_V,														/* 当前误差队列，用 ???485通讯 */
								aiError_H,														/* 横向误差队列 */
								aiFineSample_Data,												/* 计算误差细节描述-基线、最大 ?  ? 最小 ??... */
								&stStAxisParam.xOK_PosConfirmed,								/* 单标记误差确认按 ??? */
								xOK_FromMaster,													/* 单标记误差确 ???/单元盒，标志由主站 ? 讯 */
								alrThreshold,													/*  ??? ??? */
								alrBase_Fs,														/* 精采样基线 ?? */
								(BYTE*)pbyRoundData1,
								(BYTE*)pbyRoundData2,
								xFlag_SingleMode
							);
		#else

			KS_FB_ProSample(
								&stStPara_PduBroadcastUp,  										/* 通讯参数，上�??? */
								(WORD*)pbyFineData1,											/* 精采样数据地�??? */
								(WORD*)pbyFineData2,											/* 精采样数据地�??? */
								iFineSampleFlag,												/* 精采样有效标 */
								&stStAxisParam,													/* 轴参�??? */
								&stStGrpParam,													/* 系参�??? */
								alrBase,														/* 粗采样基�??? */
								aiError_V,														/* 当前误差队列，用�???485通讯 */
								aiError_H,														/* 横向误差队列 */
								aiFineSample_Data,												/* 计算误差细节描述-基线、最大�?��?�最小�??... */
								&stStAxisParam.xOK_PosConfirmed,												/* 单标记误差确认按�??? */
								xOK_FromMaster,													/* 单标记误差确�???/单元盒，标志由主站�?�讯 */
								alrThreshold,													/* �???�??? */
								alrBase_Fs,														/* 精采样基线�?? */
								(BYTE*)pbyRoundData1,
								(BYTE*)pbyRoundData2,
								xFlag_SingleMode
							);

        #endif

			/* 精采样数据处�???-计算误差 */
			if(xOK_FromMaster)															/* 单标记||2020.6.24.160749||niu.j|使用单元盒的处理 */
			{
				xOK_FromMaster = 0;
				stStAxisParam.dwControlBits &= ~(1<<4);											/* 清除bit4; */
			}
		}

		//2025.7.22.182037同步
		//485通讯赋值处理
		if(xFlag_CopyFromMaster)
		{
			KSGetScreenSaverId(&stStAxisParam,&stStGrpParam,stStPara_PduBroadcastUp.byStsV);//获取屏保id

			KS_SetData_485(//参数处理
							xUpdateRsData_Hmi,
							bySignalSelect_Cur,
							byChannel_T1T2_Cur,
							&stStGlobalParam,
							&stStAxisParam,
							&stStGrpParam,
							&g_stVisuCommData,
							aiError_V,
							aiError_H);
			KSModbusHmiComm();//通讯

			//2025.12.01.150518//xi.hy//月光宝盒Pro 自动聚焦处理
			KS_AutoFocusCtl_MoonPro(1,
									&stStGrpParam,
									&stStAxisParam,
									&stStGlobalParam,
									pbyRoundData1,				//粗采样T1_R起始地址
									pbyRoundData2,				//粗采样T2_R起始地址
									pbyRoundData3,				//粗采样T1_G起始地址
									pbyRoundData4,				//粗采样T2_G起始地址
									pbyRoundData5,				//粗采样T1_B起始地址
									pbyRoundData6,				//粗采样T2_B起始地址)
									&xFindFSPeak_SourceLightCtl,//允许从粗采样中查找峰值标志/必须在粗采样有效之后
									&g_uiTime_OffsetAutoCtl,//偏移自调控制时间计数
									&g_uiTime_xBaseDone_OffsetAutoCtl,//基线稳定多久计数
									&g_dwRemainTime_OffsetCtl,//本次调整持续时间计数
									&g_uiCtlTime_SourceLightCtl,//光源控制时间计数地址
									&g_uiTime_PeakDone_SourceAutoCtl,//光源控制到目标时间计数地址
									&g_dwRemainTime_SourceCtl);//本次光源自调持续时间计数地址

			//偏置和亮度值保护
			if(stStGlobalParam.rBias_T1<0.001) stStGlobalParam.rBias_T1=1.65;
			if(stStGlobalParam.rBias_T2<0.001) stStGlobalParam.rBias_T2=1.65;
			if(stStGlobalParam.rBrightness_Light_T1<0.001) stStGlobalParam.rBrightness_Light_T1=0.15;
			if(stStGlobalParam.rBrightness_Light_T2<0.001) stStGlobalParam.rBrightness_Light_T2=0.15;
			//光纤参数处理
			KS_FB_DacOutCtl(stStGlobalParam.rOffset_T1,
					//stStGlobalParam.rSource_Light_T1,
					stStGlobalParam.rSource_Light_T1_Cur,//2025.8.11.085426 替换
					stStGlobalParam.rBias_T1,
					stStGlobalParam.rBrightness_Light_T1,
					stStGlobalParam.rOffset_T2,
					//stStGlobalParam.rSource_Light_T2,
					stStGlobalParam.rSource_Light_T2_Cur,//2025.8.11.085426 替换
					stStGlobalParam.rBias_T2,
					stStGlobalParam.rBrightness_Light_T2);
		}

		/* >>>>>>>>>>>>>.mailbox+pdu>>>>>>>>>>>>>>>>>>>> */
		/* 等环网�?�讯 */
		/* 1.mailbox通讯-双向修改参数-波门地址、修正量 */
		/* 2.pdu通讯-单向参数-31-35#命令下行-05#上行 */
		if(g_wCount_Comm>=gc_Count_CommNum)
		{										/* 20ms计时到，进入主从站�?�讯逻辑处理 */
			/* 初始赋�??32，等待主站轴号下�???,如果初始不在1-32范围内，主从通讯逻辑进不去，�???以赋值初�???32 */
			LED0 = !LED0;//2025.12.3.143945+
			if( xStart == 0 )
			{
				xStart = 1;																/* 只做�???次初始赋�??? */
				stStAxisParam.iAxisId = 32;
			}
			/* 通讯逻辑 */
			stStAxisParam.iARMRunNum=12;		/* 2022.5.21.084425 */

			//2026.01.04.113451 给主站数字量显示使用的基线值赋值 alrBase_HMI
			alrBase_HMI[0]=stStGlobalParam.fBaseLine_T1_OffsetCtl;
			alrBase_HMI[1]=stStGlobalParam.fBaseLine_T2_OffsetCtl;
			KS_FB_SyncWithServer(/* 主从站�?�讯逻辑处理 */
									1,
									iStationId,												/* 站号 */
									1,     													/* BOOL;(*拿到Mailbox传输周期|*) */
									&xGetAxisId,
									&bySignal10VCoef,
									&byScanCount,
									&byLedSwitchTimeouts,
									//2025.09.04.170552//xi.hy
									//&iJourney_HorzRapidAdjust,       						/*2019.8.28.105803_|指向横向快�?�调整量变量|被读取以后会自动清零|*/
									&stStAxisParam.iJourney_HorzRapidAdjust,
									&stStAxisParam.dwPlateAdjustmentProf,
									&byFineSampleSaveFlag,
									&xFlag_CopyFromMaster,
									&wArmResetCount,										/* 看门狗计数�?? */
									&stStAxisParam,											/* 轴参�??? */
									&stStGrpParam,											/* 系参�??? */
									&stStGlobalParam,										/* 全局参数 */
									&stStPara_PduBroadcastUp,								/* 上行参数 */
									&stStPara_PduBroadcastDn,								/* 下行参数 */
									&stStSyncWithServerOut,
									g_iCount_TimeOutNum,
									/*2021.8.6.095337 */
									/* 2022.6.22.151624										&xSaveRead485Data, */
									&diFineSampleStart,
									alrBase_HMI,      									    /* 基线//2024.1.30.150142||不管�???么时候都是用粗采样基线去显示数字波形|Niu.j|同样给主站的基线也是这样处理 */
									g_wCnt_Rs,
									g_iRtn_Calc2022,
									g_aiVResult,
									g_aiHResult,
									&xFlag_SingleMode//,
								);
			//xInclNegative10vSignal = GetBit(stStAxisParam.wSwitchRef,9);
			xInclNegative10vSignal = KSGetDataBit(&stStAxisParam.wSwitchRef,9);
			stStGlobalParam.byMinutes_ScrAutoSleep = byLedSwitchTimeouts;//屏保延时写入@2025.7.23.200540+

			g_wCount_Comm=0;

			//在20ms周期任务中执行@2025.6.11.124050+
			//油墨槽脉冲输出控制
			pstStInkGrooveCtl = &stStAxisParam.stStInkGrooveCtl;//地址获取

			//获取通讯的数据@主->arm
			wTmp = (WORD)stStAxisParam.byPulseCtlBit;//低8bit是有效的
			//xPulseCtlEn = GetBit(wTmp,0);//脉冲控制使能
			//pstStInkGrooveCtl->byMovingSts = GetBit(wTmp,1);
			//pstStInkGrooveCtl->xMoveDir = GetBit(wTmp,2);
			//pstStInkGrooveCtl->xCtlMode = GetBit(wTmp,3);

			xPulseCtlEn = KSGetDataBit(&wTmp,0);//脉冲控制使能
			pstStInkGrooveCtl->byMovingSts = KSGetDataBit(&wTmp,1);
			pstStInkGrooveCtl->xMoveDir = KSGetDataBit(&wTmp,2);
			pstStInkGrooveCtl->xCtlMode = KSGetDataBit(&wTmp,3);

			if(pstStInkGrooveCtl->xCtlMode)//位置模式
				pstStInkGrooveCtl->rMoveDis = (REAL)stStAxisParam.wPulseCtlInf / 100;//mm
			else//速度模式
				pstStInkGrooveCtl->rVel = (REAL)stStAxisParam.wPulseCtlInf / 10;//r/min

			stStAxisParam.rInkGroovePosPPulse = (REAL)stStAxisParam.byPulseCtl_DisPerPulse/100000;//单位脉冲运动的距离@mm
			//2026.8.4.190436 /0 处理
			if(stStAxisParam.rInkGroovePosPPulse == 0)
				stStAxisParam.rInkGroovePosPPulse = 0.025;

			pstStInkGrooveCtl->diMoveDis_Pulse = (DINT)(pstStInkGrooveCtl->rMoveDis / stStAxisParam.rInkGroovePosPPulse) ;//需要运动的脉冲数
			wPulse_1r = stStAxisParam.wPulse_1r;
			if(wPulse_1r==0) wPulse_1r = 6000;
			//将上位机的控制信息重新处理
			KS_ReDealCtlCommand(
				pstStInkGrooveCtl,//通讯获取相关控制内容
				stStAxisParam.byPulseOutSts,//脉冲输出函数反馈@通讯到主站
				&xPulseOutEn_Act,
				&xMoveDir_Act,
				&xPulseCtlMode_Act,
				&xVelMod_Run_Act,
				&rVelMod_Vel_Act,
				&wPosMod_Pulse_Act,
				&stStAxisParam.xInkGrooveInPos);//通讯到主站

			//控制脉冲输出
			KS_PulseOutCtl(
				xPulseOutEn_Act,//控制脉冲输出
				xPulseCtlEn,//脉冲控制使能
				FALSE,//(*清理实际的脉冲数*)
				10,//超时计数值
				wPulse_1r,//1圈的脉冲数
				xPulseCtlMode_Act,//控制模式
				xVelMod_Run_Act,//速度模式 运动使能
				xMoveDir_Act,//方向
				(WORD)10,//起始转速没有通讯下来,写10吧
				(WORD)rVelMod_Vel_Act,//速度模式速度值
				100,//加速时间也没有通讯下来，写成100ms
				&wPosMod_Pulse_Act,//需要写入的脉冲数@0->非零才会执行
				(WORD*)&stStAxisParam.wPulse_Rd,//脉冲个数
				(BYTE*)&stStAxisParam.xPulse_Outing,//脉冲输出中标志@通讯到主站
				(BYTE*)&stStAxisParam.byPulseOutSts,//脉冲输出状态@通讯到主站
				0,
				(DINT*)&pstStInkGrooveCtl->diThisMovedPulse);//本次运动的脉冲数
		}
	}//不等于31#

//
//	else/* 站号�???31--进入以下逻辑 *///增加主站通讯完成标志
//	{
//		if((byReceiveEnd||(g_wCount_TimeOut>=gc_485_TimeoutNum)) && xFlag_CopyFromMaster)		/* 进入485通讯处理逻辑 */
//		{
//			stStAxisParam.iARMRunNum=11;		/* 2022.5.21.084425 */
//			if (g_wCount_TimeOut>=gc_485_TimeoutNum) 											/* 超时标志 */
//			{
//				g_iCount_TimeOutNum= g_iCount_TimeOutNum+1;										/* 超时计次，发送至人机显示及主站保�??? */
//			}
//			if(byReceiveEnd||(g_wCount_TimeOut>=gc_485_TimeoutNum))								/* 进入485实际发�?��?�辑 */
//			{
//				KS_FB_VISU_IF(
//								&stStGlobalParam,											    /* 全局参数相关 */
//								&stStGrpParam												    /* 系参数相�??? */
//							);
//			}
//				g_wCount_TimeOut=0;																/* �???0定时�???100ms计次 */
//				byReceiveEnd=0;
//		}
//		/* >>>>>>>>>>>>>.mailbox+pdu>>>>>>>>>>>>>>>>>>>> */
//		/* 等环网�?�讯 */
//		/* 1.mailbox通讯-双向修改参数-波门地址、修正量 */
//		/* 2.pdu通讯-单向参数-31-35#命令下行-05#上行 */
//		if(g_wCount_Comm>=gc_Count_CommNum)
//		{												/* 20ms计时到，进入主从站�?�讯逻辑处理 */
//			/* 初始赋�??32，等待主站轴号下�???,如果初始不在1-32范围内，主从通讯逻辑进不去，�???以赋值初�???32 */
//			if( xStart == 0 )
//			{
//				xStart = 1;																	/* 只做�???次初始赋�??? */
//				stStAxisParam.iAxisId = 32;
//			}
//			/* 通讯逻辑 */
//			KS_FB_SyncWithServer_Deputy(
//											1,
//											iStationId,
//											1,											/* 拿到Mailbox传输周期|*/
//											&xFlag_CopyFromMaster,						/* 获取主站参数成功标志 */
//											&stStAxisParam,								/* 轴参�??? */
//											&stStGrpParam,								/* 系参�??? */
//											&stStGlobalParam,							/* 全局参数 */
//											&stStPara_PduBroadcastUp,					/* 上行参数 */
//											&stStPara_PduBroadcastDn,					/* 下行参数 */
//											&stStSyncWithServerOut,
//											&xGetAxisId
//										);
//			g_wCount_Comm=0;
//		}
//	}

	/* 2024.02.01.154941+处理死机时�?�获取信息实现�?? */
	char xgeten = GetBit(stStAxisParam.wButtonFun,15);
	static unsigned char bygetsts_tmp;/* 备份获取状�?? */
	ks_get_prgcrash_inf(iStationId,&xgeten, &g_bygetsts,&g_getcrash_inf_timecnt_10ms,&exception_crash);
	if(g_bygetsts==3 && bygetsts_tmp !=3)/* 获取成功了，置位标志触发485通讯发�?�到人机界面�??? */
	{
		g_send_crashinf_hmi = 1;
	}
	bygetsts_tmp = g_bygetsts;
	//stStAxisParam.wButtonFun=SetBit(xgeten,stStAxisParam.wButtonFun,15);/* 更新获取的按钮位 */
	KSSetDataBit(&stStAxisParam.wButtonFun,xgeten,15);
    /* USER CODE END WHILE */

  }
}

void SystemClock_Config(void)
{
  RCC_OscInitTypeDef RCC_OscInitStruct = {0};
  RCC_ClkInitTypeDef RCC_ClkInitStruct = {0};

  /** Configure the main internal regulator output voltage
  */
  __HAL_RCC_PWR_CLK_ENABLE();
  __HAL_PWR_VOLTAGESCALING_CONFIG(PWR_REGULATOR_VOLTAGE_SCALE1);

  /** Initializes the RCC Oscillators according to the specified parameters
  * in the RCC_OscInitTypeDef structure.
  */
  RCC_OscInitStruct.OscillatorType = RCC_OSCILLATORTYPE_HSE;
  RCC_OscInitStruct.HSEState = RCC_HSE_ON;
  RCC_OscInitStruct.PLL.PLLState = RCC_PLL_ON;
  RCC_OscInitStruct.PLL.PLLSource = RCC_PLLSOURCE_HSE;
  RCC_OscInitStruct.PLL.PLLM = 25;
  RCC_OscInitStruct.PLL.PLLN = 400;
  RCC_OscInitStruct.PLL.PLLP = RCC_PLLP_DIV4;
  RCC_OscInitStruct.PLL.PLLQ = 2;
  RCC_OscInitStruct.PLL.PLLR = 2;
  if (HAL_RCC_OscConfig(&RCC_OscInitStruct) != HAL_OK)
  {
    Error_Handler();
  }

  /** Initializes the CPU, AHB and APB buses clocks
  */
  RCC_ClkInitStruct.ClockType = RCC_CLOCKTYPE_HCLK|RCC_CLOCKTYPE_SYSCLK
                              |RCC_CLOCKTYPE_PCLK1|RCC_CLOCKTYPE_PCLK2;
  RCC_ClkInitStruct.SYSCLKSource = RCC_SYSCLKSOURCE_PLLCLK;
  RCC_ClkInitStruct.AHBCLKDivider = RCC_SYSCLK_DIV1;
  //RCC_ClkInitStruct.APB1CLKDivider = RCC_HCLK_DIV2;
  //RCC_ClkInitStruct.APB2CLKDivider = RCC_HCLK_DIV1;
  //2025.11.5.124710+
  RCC_ClkInitStruct.APB1CLKDivider = RCC_HCLK_DIV4;//参考keil@4分频(25MHZ)|stm32cube 代码time3为5ms,而keil周期为10ms的原因就在这里
  RCC_ClkInitStruct.APB2CLKDivider = RCC_HCLK_DIV2;//同上

  if (HAL_RCC_ClockConfig(&RCC_ClkInitStruct, FLASH_LATENCY_3) != HAL_OK)
  {
    Error_Handler();
  }
}

void Error_Handler(void)
{
  __disable_irq();
  while (1)
  {
  }
}
